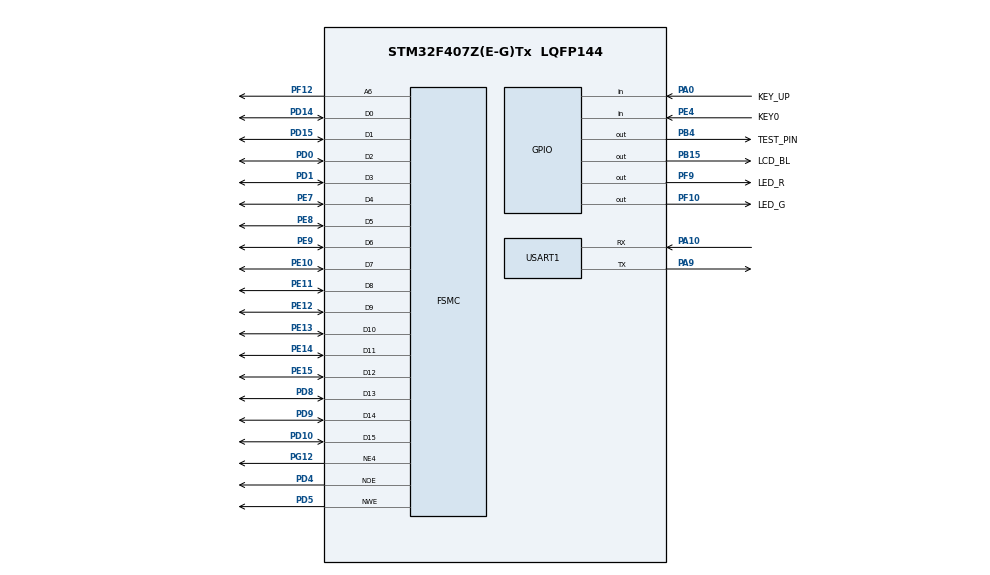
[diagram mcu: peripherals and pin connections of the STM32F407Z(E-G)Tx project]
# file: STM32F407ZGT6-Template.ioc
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FSMC.AddressSetupTime4=2
FSMC.BusTurnAroundDuration4=0
FSMC.DataSetupTime4=16
FSMC.ExtendedAddressSetupTime4=4
FSMC.ExtendedBusTurnAroundDuration4=0
FSMC.ExtendedDataSetupTime4=9
FSMC.ExtendedMode4=FSMC_EXTENDED_MODE_ENABLE
Mcu.Family=STM32F4
Mcu.Name=STM32F407Z(E-G)Tx
Mcu.Package=LQFP144
NVIC.PriorityGroup=NVIC_PRIORITYGROUP_4
NVIC.TIM7_IRQn=true\:0\:0\:false\:false\:true\:true\:true\:true
NVIC.USART1_IRQn=true\:0\:0\:false\:false\:true\:true\:true\:true
PA0-WKUP.GPIO_Label=KEY_UP
PA0-WKUP.GPIO_PuPd=GPIO_PULLDOWN
PA0-WKUP.Signal=GPIO_Input
PA10.Mode=Asynchronous
PA10.Signal=USART1_RX
PA13.Mode=Serial_Wire
PA13.Signal=SYS_JTMS-SWDIO
PA14.Mode=Serial_Wire
PA14.Signal=SYS_JTCK-SWCLK
PA9.Mode=Asynchronous
PA9.Signal=USART1_TX
PB15.GPIO_Label=LCD_BL
PB15.Signal=GPIO_Output
PB4.GPIO_Label=TEST_PIN
PB4.GPIO_ModeDefaultOutputPP=GPIO_MODE_OUTPUT_PP
PB4.GPIO_Speed=GPIO_SPEED_FREQ_HIGH
PB4.PinState=GPIO_PIN_SET
PB4.Signal=GPIO_Output
PD0.Signal=FSMC_D2_DA2
PD1.Signal=FSMC_D3_DA3
PD10.Signal=FSMC_D15_DA15
PD14.Signal=FSMC_D0_DA0
PD15.Signal=FSMC_D1_DA1
PD4.Signal=FSMC_NOE
PD5.Signal=FSMC_NWE
PD8.Signal=FSMC_D13_DA13
PD9.Signal=FSMC_D14_DA14
PE10.Signal=FSMC_D7_DA7
PE11.Signal=FSMC_D8_DA8
PE12.Signal=FSMC_D9_DA9
PE13.Signal=FSMC_D10_DA10
PE14.Signal=FSMC_D11_DA11
PE15.Signal=FSMC_D12_DA12
PE4.GPIO_Label=KEY0
PE4.GPIO_PuPd=GPIO_PULLDOWN
PE4.Signal=GPIO_Input
PE7.Signal=FSMC_D4_DA4
PE8.Signal=FSMC_D5_DA5
PE9.Signal=FSMC_D6_DA6
PF10.GPIO_Label=LED_G
PF10.GPIO_PuPd=GPIO_PULLUP
PF10.PinState=GPIO_PIN_SET
PF10.Signal=GPIO_Output
PF12.Signal=FSMC_A6
PF9.GPIO_Label=LED_R
PF9.GPIO_PuPd=GPIO_PULLUP
PF9.PinState=GPIO_PIN_SET
PF9.Signal=GPIO_Output
PG12.Mode=NorPsramChipSelect4_4
PG12.Signal=FSMC_NE4
PH0-OSC_IN.Mode=HSE-External-Oscillator
PH0-OSC_IN.Signal=RCC_OSC_IN
PH1-OSC_OUT.Mode=HSE-External-Oscillator
PH1-OSC_OUT.Signal=RCC_OSC_OUT
ProjectManager.HeapSize=0x200
ProjectManager.StackSize=0x400
ProjectManager.TargetToolchain=MDK-ARM V5.27
RCC.48MHZClocksFreq_Value=12000000
RCC.AHBFreq_Value=72000000
RCC.APB1CLKDivider=RCC_HCLK_DIV2
RCC.APB1Freq_Value=36000000
RCC.APB1TimFreq_Value=72000000
RCC.APB2Freq_Value=72000000
RCC.APB2TimFreq_Value=72000000
RCC.CortexFreq_Value=72000000
RCC.FLatency=FLASH_LATENCY_2
RCC.HCLKFreq_Value=72000000
RCC.HSE_VALUE=8000000
RCC.HSI_VALUE=16000000
RCC.LSE_VALUE=32768
RCC.PLLM=4
RCC.PLLN=72
RCC.PLLQ=12
RCC.PLLSourceVirtual=RCC_PLLSOURCE_HSE
RCC.SYSCLKFreq_VALUE=72000000
RCC.SYSCLKSource=RCC_SYSCLKSOURCE_PLLCLK
RCC.VCOOutputFreq_Value=144000000
SH.FSMC_A6.0=FSMC_A6,A6_4
SH.FSMC_D0_DA0.0=FSMC_D0,16b-d4
SH.FSMC_D10_DA10.0=FSMC_D10,16b-d4
SH.FSMC_D11_DA11.0=FSMC_D11,16b-d4
SH.FSMC_D12_DA12.0=FSMC_D12,16b-d4
SH.FSMC_D13_DA13.0=FSMC_D13,16b-d4
SH.FSMC_D14_DA14.0=FSMC_D14,16b-d4
SH.FSMC_D15_DA15.0=FSMC_D15,16b-d4
SH.FSMC_D1_DA1.0=FSMC_D1,16b-d4
SH.FSMC_D2_DA2.0=FSMC_D2,16b-d4
SH.FSMC_D3_DA3.0=FSMC_D3,16b-d4
SH.FSMC_D4_DA4.0=FSMC_D4,16b-d4
SH.FSMC_D5_DA5.0=FSMC_D5,16b-d4
SH.FSMC_D6_DA6.0=FSMC_D6,16b-d4
SH.FSMC_D7_DA7.0=FSMC_D7,16b-d4
SH.FSMC_D8_DA8.0=FSMC_D8,16b-d4
SH.FSMC_D9_DA9.0=FSMC_D9,16b-d4
SH.FSMC_NOE.0=FSMC_NOE,Lcd4
SH.FSMC_NWE.0=FSMC_NWE,Lcd4
TIM6.Period=10000
TIM6.Prescaler=84
TIM7.Period=10000-1
TIM7.Prescaler=8400-1
USART1.VirtualMode=VM_ASYNC
VP_RNG_VS_RNG.Mode=RNG_Activate
VP_TIM6_VS_ClockSourceINT.Mode=Enable_Timer
VP_TIM7_VS_ClockSourceINT.Mode=Enable_Timer
board=custom

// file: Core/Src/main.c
/* USER CODE BEGIN Header */
/**
  ******************************************************************************
  * @file           : main.c
  * @brief          : Main program body
  ******************************************************************************
  * @attention
  *
  * Copyright (c) 2023 STMicroelectronics.
  * All rights reserved.
  *
  * This software is licensed under terms that can be found in the LICENSE file
  * in the root directory of this software component.
  * If no LICENSE file comes with this software, it is provided AS-IS.
  *
  ******************************************************************************
  */
/* USER CODE END Header */
#include "main.h"
#include "rng.h"
#include "tim.h"
#include "usart.h"
#include "gpio.h"
#include "fsmc.h"

/* USER CODE BEGIN PV */
uint8_t idle_rec_buf[100];
/* USER CODE END PV */

void SystemClock_Config(void);

int main(void)
{

  /* MCU Configuration--------------------------------------------------------*/

  /* Reset of all peripherals, Initializes the Flash interface and the Systick. */
  HAL_Init();

  /* Configure the system clock */
  SystemClock_Config();

  /* Initialize all configured peripherals */
  MX_GPIO_Init();
  MX_USART1_UART_Init();
  MX_TIM7_Init();
  MX_RNG_Init();
  MX_FSMC_Init();
  MX_TIM6_Init();
  /* USER CODE BEGIN 2 */

	lcd_init(0, RED);
	printf("程序功能:LCD按下KEY_UP刷屏\r\n");
//	HAL_TIM_Base_Start_IT(&htim7);

	HAL_UARTEx_ReceiveToIdle_IT(&huart1, idle_rec_buf, 100);	/* 每次使用发生中断后不会自动恢复,要再次使用这个函数 */
  /* USER CODE END 2 */

  /* Infinite loop */
  /* USER CODE BEGIN WHILE */
  while (1)
  {
		uint8_t key = Get_key_with_undo(20);
		if(key == key_up_down)
		{
			uint16_t num = RNG_GetRandomNumber(10000, 65535);
			lcd_clear(num);
		}
		if(key == key0_down)
		{

		}

    /* USER CODE END WHILE */

  }
}

void SystemClock_Config(void)
{
  RCC_OscInitTypeDef RCC_OscInitStruct = {0};
  RCC_ClkInitTypeDef RCC_ClkInitStruct = {0};

  /** Configure the main internal regulator output voltage
  */
  __HAL_RCC_PWR_CLK_ENABLE();
  __HAL_PWR_VOLTAGESCALING_CONFIG(PWR_REGULATOR_VOLTAGE_SCALE1);

  /** Initializes the RCC Oscillators according to the specified parameters
  * in the RCC_OscInitTypeDef structure.
  */
  RCC_OscInitStruct.OscillatorType = RCC_OSCILLATORTYPE_HSE;
  RCC_OscInitStruct.HSEState = RCC_HSE_ON;
  RCC_OscInitStruct.PLL.PLLState = RCC_PLL_ON;
  RCC_OscInitStruct.PLL.PLLSource = RCC_PLLSOURCE_HSE;
  RCC_OscInitStruct.PLL.PLLM = 4;
  RCC_OscInitStruct.PLL.PLLN = 168;
  RCC_OscInitStruct.PLL.PLLP = RCC_PLLP_DIV2;
  RCC_OscInitStruct.PLL.PLLQ = 7;
  if (HAL_RCC_OscConfig(&RCC_OscInitStruct) != HAL_OK)
  {
    Error_Handler();
  }

  /** Initializes the CPU, AHB and APB buses clocks
  */
  RCC_ClkInitStruct.ClockType = RCC_CLOCKTYPE_HCLK|RCC_CLOCKTYPE_SYSCLK
                              |RCC_CLOCKTYPE_PCLK1|RCC_CLOCKTYPE_PCLK2;
  RCC_ClkInitStruct.SYSCLKSource = RCC_SYSCLKSOURCE_PLLCLK;
  RCC_ClkInitStruct.AHBCLKDivider = RCC_SYSCLK_DIV1;
  RCC_ClkInitStruct.APB1CLKDivider = RCC_HCLK_DIV4;
  RCC_ClkInitStruct.APB2CLKDivider = RCC_HCLK_DIV2;

  if (HAL_RCC_ClockConfig(&RCC_ClkInitStruct, FLASH_LATENCY_5) != HAL_OK)
  {
    Error_Handler();
  }
}

/* USER CODE BEGIN 4 */

/* 定时器回调函数 */
void HAL_TIM_PeriodElapsedCallback(TIM_HandleTypeDef *htim)
{
	/* 定时一秒 */
	if(htim == &htim7)
	{

	}
}

/* 串口IDLE中断函数 */
void HAL_UARTEx_RxEventCallback(UART_HandleTypeDef *huart, uint16_t Size)
{
	if(huart == &huart1)
	{
		idle_rec_buf[Size] = '\0';

		HAL_UART_Transmit(&huart1, idle_rec_buf, strlen((char*)idle_rec_buf), 0xff);

		HAL_UARTEx_ReceiveToIdle_IT(&huart1, idle_rec_buf, 100);	/* 再次打开串口IDLE中断接收函数 */
	}
}
/* USER CODE END 4 */

void Error_Handler(void)
{
  __disable_irq();
  while (1)
  {
  }
}
